One B-rep face of a CAD part: STEP entity #35.
In plain terms, the cylindrical face has radius 8 mm (diameter 16 mm), a full revolution.
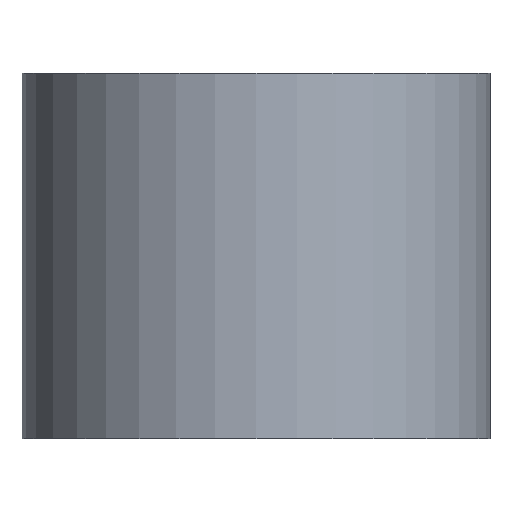
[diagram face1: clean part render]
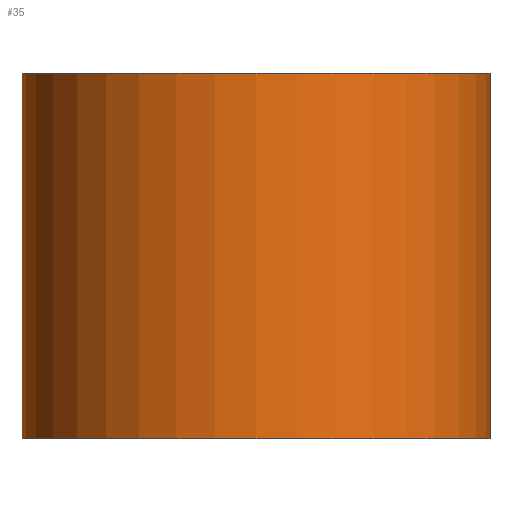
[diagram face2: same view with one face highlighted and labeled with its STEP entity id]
Its self-contained STEP definition (entity closure, numbers rounded to 3 decimals):
#35 = ADVANCED_FACE('',(#36),#49,.T.);
#36 = FACE_BOUND('',#37,.T.);
#37 = EDGE_LOOP('',(#38,#72,#95,#122));
#38 = ORIENTED_EDGE('',*,*,#39,.T.);
#39 = EDGE_CURVE('',#40,#40,#42,.T.);
#40 = VERTEX_POINT('',#41);
#41 = CARTESIAN_POINT('',(8.,0.,-12.5));
#42 = SURFACE_CURVE('',#43,(#48,#60),.PCURVE_S1.);
#43 = CIRCLE('',#44,8.);
#44 = AXIS2_PLACEMENT_3D('',#45,#46,#47);
#45 = CARTESIAN_POINT('',(0.,0.,-12.5));
#46 = DIRECTION('',(0.,0.,1.));
#47 = DIRECTION('',(1.,0.,-0.));
#48 = PCURVE('',#49,#54);
#49 = CYLINDRICAL_SURFACE('',#50,8.);
#50 = AXIS2_PLACEMENT_3D('',#51,#52,#53);
#51 = CARTESIAN_POINT('',(0.,0.,-12.5));
#52 = DIRECTION('',(-0.,-0.,-1.));
#53 = DIRECTION('',(1.,0.,0.));
#54 = DEFINITIONAL_REPRESENTATION('',(#55),#59);
#55 = LINE('',#56,#57);
#56 = CARTESIAN_POINT('',(6.283,0.));
#57 = VECTOR('',#58,1.);
#58 = DIRECTION('',(-1.,0.));
#59 = ( GEOMETRIC_REPRESENTATION_CONTEXT(2) 
PARAMETRIC_REPRESENTATION_CONTEXT() REPRESENTATION_CONTEXT('2D SPACE',''
  ) );
#60 = PCURVE('',#61,#66);
#61 = PLANE('',#62);
#62 = AXIS2_PLACEMENT_3D('',#63,#64,#65);
#63 = CARTESIAN_POINT('',(0.,0.,-12.5)
  );
#64 = DIRECTION('',(0.,0.,1.));
#65 = DIRECTION('',(1.,0.,-0.));
#66 = DEFINITIONAL_REPRESENTATION('',(#67),#71);
#67 = CIRCLE('',#68,8.);
#68 = AXIS2_PLACEMENT_2D('',#69,#70);
#69 = CARTESIAN_POINT('',(0.,0.));
#70 = DIRECTION('',(1.,0.));
#71 = ( GEOMETRIC_REPRESENTATION_CONTEXT(2) 
PARAMETRIC_REPRESENTATION_CONTEXT() REPRESENTATION_CONTEXT('2D SPACE',''
  ) );
#72 = ORIENTED_EDGE('',*,*,#73,.T.);
#73 = EDGE_CURVE('',#40,#74,#76,.T.);
#74 = VERTEX_POINT('',#75);
#75 = CARTESIAN_POINT('',(8.,0.,0.));
#76 = SEAM_CURVE('',#77,(#81,#88),.PCURVE_S1.);
#77 = LINE('',#78,#79);
#78 = CARTESIAN_POINT('',(8.,0.,-12.5));
#79 = VECTOR('',#80,1.);
#80 = DIRECTION('',(0.,0.,1.));
#81 = PCURVE('',#49,#82);
#82 = DEFINITIONAL_REPRESENTATION('',(#83),#87);
#83 = LINE('',#84,#85);
#84 = CARTESIAN_POINT('',(0.,0.));
#85 = VECTOR('',#86,1.);
#86 = DIRECTION('',(-0.,-1.));
#87 = ( GEOMETRIC_REPRESENTATION_CONTEXT(2) 
PARAMETRIC_REPRESENTATION_CONTEXT() REPRESENTATION_CONTEXT('2D SPACE',''
  ) );
#88 = PCURVE('',#49,#89);
#89 = DEFINITIONAL_REPRESENTATION('',(#90),#94);
#90 = LINE('',#91,#92);
#91 = CARTESIAN_POINT('',(6.283,0.));
#92 = VECTOR('',#93,1.);
#93 = DIRECTION('',(-0.,-1.));
#94 = ( GEOMETRIC_REPRESENTATION_CONTEXT(2) 
PARAMETRIC_REPRESENTATION_CONTEXT() REPRESENTATION_CONTEXT('2D SPACE',''
  ) );
#95 = ORIENTED_EDGE('',*,*,#96,.F.);
#96 = EDGE_CURVE('',#74,#74,#97,.T.);
#97 = SURFACE_CURVE('',#98,(#103,#110),.PCURVE_S1.);
#98 = CIRCLE('',#99,8.);
#99 = AXIS2_PLACEMENT_3D('',#100,#101,#102);
#100 = CARTESIAN_POINT('',(0.,0.,0.));
#101 = DIRECTION('',(0.,0.,1.));
#102 = DIRECTION('',(1.,0.,-0.));
#103 = PCURVE('',#49,#104);
#104 = DEFINITIONAL_REPRESENTATION('',(#105),#109);
#105 = LINE('',#106,#107);
#106 = CARTESIAN_POINT('',(6.283,-12.5));
#107 = VECTOR('',#108,1.);
#108 = DIRECTION('',(-1.,0.));
#109 = ( GEOMETRIC_REPRESENTATION_CONTEXT(2) 
PARAMETRIC_REPRESENTATION_CONTEXT() REPRESENTATION_CONTEXT('2D SPACE',''
  ) );
#110 = PCURVE('',#111,#116);
#111 = PLANE('',#112);
#112 = AXIS2_PLACEMENT_3D('',#113,#114,#115);
#113 = CARTESIAN_POINT('',(0.,0.,0.));
#114 = DIRECTION('',(0.,0.,1.));
#115 = DIRECTION('',(1.,0.,-0.));
#116 = DEFINITIONAL_REPRESENTATION('',(#117),#121);
#117 = CIRCLE('',#118,8.);
#118 = AXIS2_PLACEMENT_2D('',#119,#120);
#119 = CARTESIAN_POINT('',(0.,0.));
#120 = DIRECTION('',(1.,0.));
#121 = ( GEOMETRIC_REPRESENTATION_CONTEXT(2) 
PARAMETRIC_REPRESENTATION_CONTEXT() REPRESENTATION_CONTEXT('2D SPACE',''
  ) );
#122 = ORIENTED_EDGE('',*,*,#73,.F.);
